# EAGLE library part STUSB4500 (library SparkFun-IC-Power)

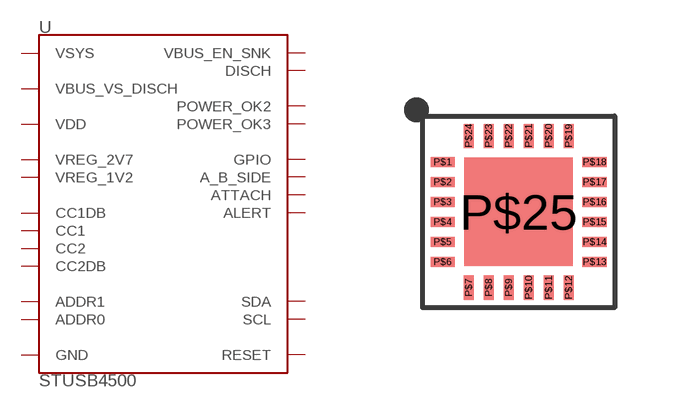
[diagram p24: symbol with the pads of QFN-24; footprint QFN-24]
Designator prefix U

## STUSB4500 (PROD_ID: IC-14684; VALUE: STUSB4500)  [QFN-24]
P$1  CC1DB
P$2  CC1
P$4  CC2
P$5  CC2DB
P$6  RESET
P$7  SCL
P$8  SDA
P$9  DISCH
P$10  GND
P$11  ATTACH
P$12  ADDR0
P$13  ADDR1
P$14  POWER_OK3
P$15  GPIO
P$16  VBUS_EN_SNK
P$17  A_B_SIDE
P$18  VBUS_VS_DISCH
P$19  ALERT
P$20  POWER_OK2
P$21  VREG_1V2
P$22  VSYS
P$23  VREG_2V7
P$24  VDD
P$25  GND

## Footprint QFN-24 (pad centres in mm)
smd 0.6 x 0.25: P$1 -1.9,1.25; P$2 -1.9,0.75; P$3 -1.9,0.25; P$4 -1.9,-0.25; P$5 -1.9,-0.75; P$6 -1.9,-1.25; P$13 1.9,-1.25; P$14 1.9,-0.75; P$15 1.9,-0.25; P$16 1.9,0.25; P$17 1.9,0.75; P$18 1.9,1.25
smd 0.25 x 0.6: P$7 -1.25,-1.9; P$8 -0.75,-1.9; P$9 -0.25,-1.9; P$10 0.25,-1.9; P$11 0.75,-1.9; P$12 1.25,-1.9; P$19 1.25,1.9; P$20 0.75,1.9; P$21 0.25,1.9; P$22 -0.25,1.9; P$23 -0.75,1.9; P$24 -1.25,1.9
smd 2.7 x 2.7: P$25 0,0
